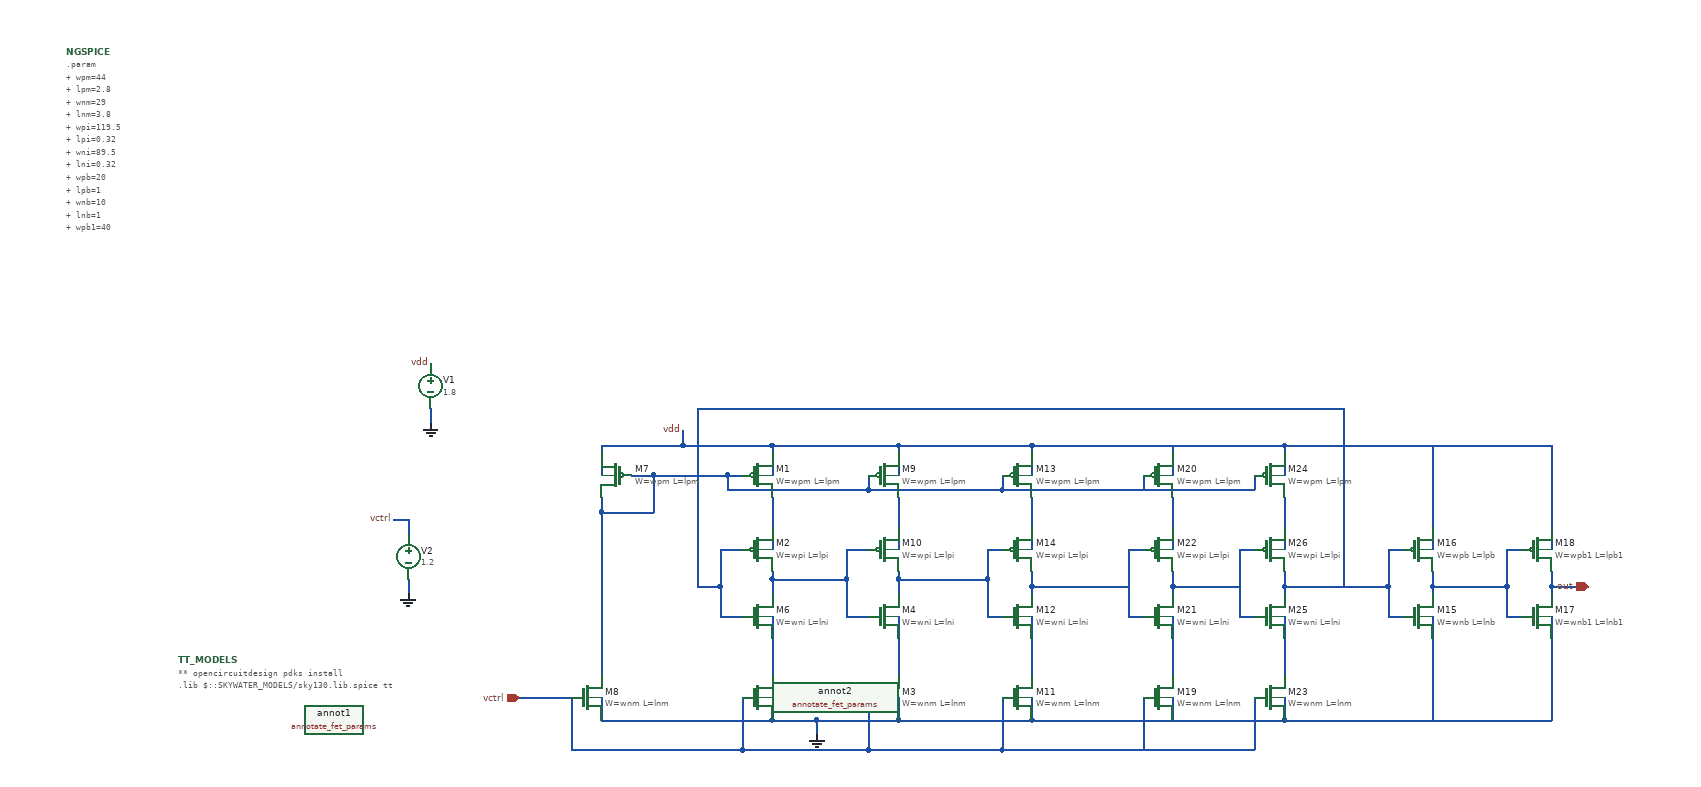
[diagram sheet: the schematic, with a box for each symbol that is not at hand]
v {xschem version=3.4.8RC file_version=1.3}
G {}
K {}
V {}
S {}
F {}
E {}
B 2 1400 -140 2200 260 {flags=graph
y1=-0.039
y2=1.9
ypos1=0
ypos2=2
divy=5
subdivy=1
unity=1
x1=7.7426134e-07
x2=8.4463009e-07
divx=5
subdivx=1
xlabmag=1.0
ylabmag=1.0
node=out
color=4
dataset=-1
unitx=1
logx=0
logy=0
hilight_wave=0}
N 1110 560 1110 580 {lab=#net1}
N 1110 450 1110 520 {lab=#net2}
N 1040 570 1040 610 {lab=#net3}
N 1040 520 1070 520 {lab=#net3}
N 1050 420 1070 420 {lab=#net4}
N 880 470 950 470 {lab=#net4}
N 950 420 950 470 {lab=#net4}
N 1070 720 1070 790 {lab=vctrl}
N 840 720 840 790 {lab=vctrl}
N 770 720 840 720 {lab=vctrl}
N 880 720 880 750 {lab=0}
N 880 750 1110 750 {lab=0}
N 1110 720 1110 750 {lab=0}
N 1040 610 1070 610 {lab=#net3}
N 880 380 880 420 {lab=vdd}
N 990 380 1110 380 {lab=vdd}
N 1110 380 1110 420 {lab=vdd}
N 1280 450 1280 520 {lab=#net5}
N 1240 720 1240 790 {lab=vctrl}
N 1280 720 1280 750 {lab=0}
N 1280 380 1280 420 {lab=vdd}
N 1110 560 1210 560 {lab=#net1}
N 1210 520 1210 560 {lab=#net1}
N 1210 520 1240 520 {lab=#net1}
N 1210 560 1210 610 {lab=#net1}
N 1210 610 1240 610 {lab=#net1}
N 1110 380 1280 380 {lab=vdd}
N 1460 450 1460 520 {lab=#net6}
N 1420 720 1420 790 {lab=vctrl}
N 1460 720 1460 750 {lab=0}
N 1460 380 1460 420 {lab=vdd}
N 1280 560 1400 560 {lab=#net7}
N 1400 520 1400 560 {lab=#net7}
N 1400 520 1420 520 {lab=#net7}
N 1400 560 1400 610 {lab=#net7}
N 1400 610 1420 610 {lab=#net7}
N 1540 570 1580 570 {lab=#net8}
N 1010 330 1010 570 {lab=#net3}
N 1010 570 1040 570 {lab=#net3}
N 1280 750 1460 750 {lab=0}
N 1240 790 1420 790 {lab=vctrl}
N 880 470 880 690 {lab=#net4}
N 990 360 990 380 {lab=vdd}
N 1280 380 1460 380 {lab=vdd}
N 1110 610 1110 700 {lab=#net9}
N 650 330 650 350 {lab=0}
N 600 480 620 480 {lab=vctrl}
N 620 480 620 500 {lab=vctrl}
N 620 560 620 580 {lab=0}
N 1050 420 1050 440 {lab=#net4}
N 1050 440 1240 440 {lab=#net4}
N 1240 420 1240 440 {lab=#net4}
N 1240 440 1420 440 {lab=#net4}
N 1420 420 1420 440 {lab=#net4}
N 1280 560 1280 580 {lab=#net7}
N 1280 610 1280 700 {lab=#net10}
N 1460 570 1460 580 {lab=#net8}
N 1460 610 1460 700 {lab=#net11}
N 1460 380 1640 380 {lab=vdd}
N 1010 330 1540 330 {lab=#net3}
N 1640 380 1800 380 {lab=vdd}
N 1640 750 1800 750 {lab=0}
N 880 450 880 470 {lab=#net4}
N 920 420 950 420 {lab=#net4}
N 840 790 1070 790 {lab=vctrl}
N 880 380 990 380 {lab=vdd}
N 1070 790 1240 790 {lab=vctrl}
N 1170 750 1280 750 {lab=0}
N 1110 550 1110 560 {lab=#net1}
N 1280 550 1280 560 {lab=#net7}
N 1460 550 1460 570 {lab=#net8}
N 1040 520 1040 570 {lab=#net3}
N 1110 750 1170 750 {lab=0}
N 950 420 1050 420 {lab=#net4}
N 1460 570 1540 570 {lab=#net8}
N 1460 750 1640 750 {lab=0}
N 1170 750 1170 770 {lab=0}
N 1940 520 1940 570 {lab=#net3}
N 1940 520 1960 520 {lab=#net3}
N 1940 570 1940 610 {lab=#net3}
N 1940 610 1960 610 {lab=#net3}
N 2000 570 2000 580 {lab=#net12}
N 2000 570 2100 570 {lab=#net12}
N 2100 520 2100 570 {lab=#net12}
N 2100 520 2120 520 {lab=#net12}
N 2100 570 2100 610 {lab=#net12}
N 2100 610 2120 610 {lab=#net12}
N 2160 570 2160 580 {lab=out}
N 2160 570 2210 570 {lab=out}
N 2000 550 2000 570 {lab=#net12}
N 2160 550 2160 570 {lab=out}
N 1650 450 1650 520 {lab=#net13}
N 1610 720 1610 790 {lab=vctrl}
N 1650 720 1650 750 {lab=0}
N 1650 380 1650 420 {lab=vdd}
N 1590 520 1590 560 {lab=#net8}
N 1590 520 1610 520 {lab=#net8}
N 1590 560 1590 610 {lab=#net8}
N 1590 610 1610 610 {lab=#net8}
N 1610 420 1610 440 {lab=#net4}
N 1650 570 1650 580 {lab=#net14}
N 1650 610 1650 700 {lab=#net15}
N 1650 550 1650 570 {lab=#net14}
N 1800 450 1800 520 {lab=#net16}
N 1760 720 1760 790 {lab=vctrl}
N 1800 720 1800 750 {lab=0}
N 1800 380 1800 420 {lab=vdd}
N 1740 520 1740 560 {lab=#net14}
N 1740 520 1760 520 {lab=#net14}
N 1740 560 1740 610 {lab=#net14}
N 1740 610 1760 610 {lab=#net14}
N 1760 420 1760 440 {lab=#net4}
N 1800 570 1800 580 {lab=#net3}
N 1800 610 1800 700 {lab=#net17}
N 1800 550 1800 570 {lab=#net3}
N 1800 570 1940 570 {lab=#net3}
N 1800 380 2160 380 {lab=vdd}
N 2160 380 2160 490 {lab=vdd}
N 2000 380 2000 490 {lab=vdd}
N 2000 490 2000 520 {lab=vdd}
N 2160 490 2160 520 {lab=vdd}
N 2000 610 2000 640 {lab=0}
N 2160 610 2160 640 {lab=0}
N 1800 750 2160 750 {lab=0}
N 2160 640 2160 750 {lab=0}
N 2000 640 2000 750 {lab=0}
N 1420 790 1760 790 {lab=vctrl}
N 1420 440 1760 440 {lab=#net4}
N 1580 570 1590 570 {lab=#net8}
N 1650 570 1740 570 {lab=#net14}
N 1880 330 1880 570 {lab=#net3}
N 1540 330 1880 330 {lab=#net3}
C {sky130_fd_pr/pfet_01v8.sym} 900 420 0 1 {name=M7
W="wpm"
L="lpm"
nf=1
mult=1
ad="expr('int((@nf + 1)/2) * @W / @nf * 0.29')"
pd="expr('2*int((@nf + 1)/2) * (@W / @nf + 0.29)')"
as="expr('int((@nf + 2)/2) * @W / @nf * 0.29')"
ps="expr('2*int((@nf + 2)/2) * (@W / @nf + 0.29)')"
nrd="expr('0.29 / @W ')" nrs="expr('0.29 / @W ')"
sa=0 sb=0 sd=0
model=pfet_01v8
spiceprefix=X
}
C {sky130_fd_pr/nfet_01v8.sym} 860 720 0 0 {name=M8
W="wnm"
L="lnm"
nf=1 
mult=1
ad="expr('int((@nf + 1)/2) * @W / @nf * 0.29')"
pd="expr('2*int((@nf + 1)/2) * (@W / @nf + 0.29)')"
as="expr('int((@nf + 2)/2) * @W / @nf * 0.29')"
ps="expr('2*int((@nf + 2)/2) * (@W / @nf + 0.29)')"
nrd="expr('0.29 / @W ')" nrs="expr('0.29 / @W ')"
sa=0 sb=0 sd=0
model=nfet_01v8
spiceprefix=X
}
C {sky130_fd_pr/nfet_01v8.sym} 1090 720 0 0 {name=M5
W="wnm"
L="lnm"
nf=1 
mult=1
ad="expr('int((@nf + 1)/2) * @W / @nf * 0.29')"
pd="expr('2*int((@nf + 1)/2) * (@W / @nf + 0.29)')"
as="expr('int((@nf + 2)/2) * @W / @nf * 0.29')"
ps="expr('2*int((@nf + 2)/2) * (@W / @nf + 0.29)')"
nrd="expr('0.29 / @W ')" nrs="expr('0.29 / @W ')"
sa=0 sb=0 sd=0
model=nfet_01v8
spiceprefix=X
}
C {sky130_fd_pr/nfet_01v8.sym} 1090 610 0 0 {name=M6
W="wni"
L="lni"
nf=1 
mult=1
ad="expr('int((@nf + 1)/2) * @W / @nf * 0.29')"
pd="expr('2*int((@nf + 1)/2) * (@W / @nf + 0.29)')"
as="expr('int((@nf + 2)/2) * @W / @nf * 0.29')"
ps="expr('2*int((@nf + 2)/2) * (@W / @nf + 0.29)')"
nrd="expr('0.29 / @W ')" nrs="expr('0.29 / @W ')"
sa=0 sb=0 sd=0
model=nfet_01v8
spiceprefix=X
}
C {sky130_fd_pr/pfet_01v8.sym} 1090 420 0 0 {name=M1
W="wpm"
L="lpm"
nf=1
mult=1
ad="expr('int((@nf + 1)/2) * @W / @nf * 0.29')"
pd="expr('2*int((@nf + 1)/2) * (@W / @nf + 0.29)')"
as="expr('int((@nf + 2)/2) * @W / @nf * 0.29')"
ps="expr('2*int((@nf + 2)/2) * (@W / @nf + 0.29)')"
nrd="expr('0.29 / @W ')" nrs="expr('0.29 / @W ')"
sa=0 sb=0 sd=0
model=pfet_01v8
spiceprefix=X
}
C {sky130_fd_pr/pfet_01v8.sym} 1090 520 0 0 {name=M2
W="wpi"
L="lpi"
nf=1
mult=1
ad="expr('int((@nf + 1)/2) * @W / @nf * 0.29')"
pd="expr('2*int((@nf + 1)/2) * (@W / @nf + 0.29)')"
as="expr('int((@nf + 2)/2) * @W / @nf * 0.29')"
ps="expr('2*int((@nf + 2)/2) * (@W / @nf + 0.29)')"
nrd="expr('0.29 / @W ')" nrs="expr('0.29 / @W ')"
sa=0 sb=0 sd=0
model=pfet_01v8
spiceprefix=X
}
C {sky130_fd_pr/nfet_01v8.sym} 1260 720 0 0 {name=M3
W="wnm"
L="lnm"
nf=1 
mult=1
ad="expr('int((@nf + 1)/2) * @W / @nf * 0.29')"
pd="expr('2*int((@nf + 1)/2) * (@W / @nf + 0.29)')"
as="expr('int((@nf + 2)/2) * @W / @nf * 0.29')"
ps="expr('2*int((@nf + 2)/2) * (@W / @nf + 0.29)')"
nrd="expr('0.29 / @W ')" nrs="expr('0.29 / @W ')"
sa=0 sb=0 sd=0
model=nfet_01v8
spiceprefix=X
}
C {sky130_fd_pr/pfet_01v8.sym} 1260 420 0 0 {name=M9
W="wpm"
L="lpm"
nf=1
mult=1
ad="expr('int((@nf + 1)/2) * @W / @nf * 0.29')"
pd="expr('2*int((@nf + 1)/2) * (@W / @nf + 0.29)')"
as="expr('int((@nf + 2)/2) * @W / @nf * 0.29')"
ps="expr('2*int((@nf + 2)/2) * (@W / @nf + 0.29)')"
nrd="expr('0.29 / @W ')" nrs="expr('0.29 / @W ')"
sa=0 sb=0 sd=0
model=pfet_01v8
spiceprefix=X
}
C {sky130_fd_pr/nfet_01v8.sym} 1440 720 0 0 {name=M11
W="wnm"
L="lnm"
nf=1 
mult=1
ad="expr('int((@nf + 1)/2) * @W / @nf * 0.29')"
pd="expr('2*int((@nf + 1)/2) * (@W / @nf + 0.29)')"
as="expr('int((@nf + 2)/2) * @W / @nf * 0.29')"
ps="expr('2*int((@nf + 2)/2) * (@W / @nf + 0.29)')"
nrd="expr('0.29 / @W ')" nrs="expr('0.29 / @W ')"
sa=0 sb=0 sd=0
model=nfet_01v8
spiceprefix=X
}
C {sky130_fd_pr/pfet_01v8.sym} 1440 420 0 0 {name=M13
W="wpm"
L="lpm"
nf=1
mult=1
ad="expr('int((@nf + 1)/2) * @W / @nf * 0.29')"
pd="expr('2*int((@nf + 1)/2) * (@W / @nf + 0.29)')"
as="expr('int((@nf + 2)/2) * @W / @nf * 0.29')"
ps="expr('2*int((@nf + 2)/2) * (@W / @nf + 0.29)')"
nrd="expr('0.29 / @W ')" nrs="expr('0.29 / @W ')"
sa=0 sb=0 sd=0
model=pfet_01v8
spiceprefix=X
}
C {ipin.sym} 770 720 0 0 {name=p1 lab=vctrl}
C {code_shown.sym} 160 -150 0 0 {name=NGSPICE only_toplevel=false value="
.param
+ wpm=44
+ lpm=2.8
+ wnm=29
+ lnm=3.8
+ wpi=119.5
+ lpi=0.32
+ wni=89.5
+ lni=0.32
+ wpb=20
+ lpb=1
+ wnb=10
+ lnb=1
+ wpb1=40
+ lpb1=1
+ wnb1=20
+ lnb1=1
.control
tran 1n 2u
write vco_5.raw
.endc
"}
C {gnd.sym} 1170 770 0 0 {name=l2 lab=0}
C {vsource.sym} 650 300 0 0 {name=V1 value=1.8 savecurrent=false}
C {lab_pin.sym} 650 270 0 0 {name=p4 sig_type=std_logic lab=vdd}
C {gnd.sym} 650 350 0 0 {name=l3 lab=0}
C {vsource.sym} 620 530 0 0 {name=V2 value=1.2 savecurrent=false}
C {gnd.sym} 620 580 0 0 {name=l4 lab=0}
C {sky130_fd_pr/nfet_01v8.sym} 1260 610 0 0 {name=M4
W="wni"
L="lni"
nf=1 
mult=1
ad="expr('int((@nf + 1)/2) * @W / @nf * 0.29')"
pd="expr('2*int((@nf + 1)/2) * (@W / @nf + 0.29)')"
as="expr('int((@nf + 2)/2) * @W / @nf * 0.29')"
ps="expr('2*int((@nf + 2)/2) * (@W / @nf + 0.29)')"
nrd="expr('0.29 / @W ')" nrs="expr('0.29 / @W ')"
sa=0 sb=0 sd=0
model=nfet_01v8
spiceprefix=X
}
C {sky130_fd_pr/pfet_01v8.sym} 1260 520 0 0 {name=M10
W="wpi"
L="lpi"
nf=1
mult=1
ad="expr('int((@nf + 1)/2) * @W / @nf * 0.29')"
pd="expr('2*int((@nf + 1)/2) * (@W / @nf + 0.29)')"
as="expr('int((@nf + 2)/2) * @W / @nf * 0.29')"
ps="expr('2*int((@nf + 2)/2) * (@W / @nf + 0.29)')"
nrd="expr('0.29 / @W ')" nrs="expr('0.29 / @W ')"
sa=0 sb=0 sd=0
model=pfet_01v8
spiceprefix=X
}
C {sky130_fd_pr/nfet_01v8.sym} 1440 610 0 0 {name=M12
W="wni"
L="lni"
nf=1 
mult=1
ad="expr('int((@nf + 1)/2) * @W / @nf * 0.29')"
pd="expr('2*int((@nf + 1)/2) * (@W / @nf + 0.29)')"
as="expr('int((@nf + 2)/2) * @W / @nf * 0.29')"
ps="expr('2*int((@nf + 2)/2) * (@W / @nf + 0.29)')"
nrd="expr('0.29 / @W ')" nrs="expr('0.29 / @W ')"
sa=0 sb=0 sd=0
model=nfet_01v8
spiceprefix=X
}
C {sky130_fd_pr/pfet_01v8.sym} 1440 520 0 0 {name=M14
W="wpi"
L="lpi"
nf=1
mult=1
ad="expr('int((@nf + 1)/2) * @W / @nf * 0.29')"
pd="expr('2*int((@nf + 1)/2) * (@W / @nf + 0.29)')"
as="expr('int((@nf + 2)/2) * @W / @nf * 0.29')"
ps="expr('2*int((@nf + 2)/2) * (@W / @nf + 0.29)')"
nrd="expr('0.29 / @W ')" nrs="expr('0.29 / @W ')"
sa=0 sb=0 sd=0
model=pfet_01v8
spiceprefix=X
}
C {lab_pin.sym} 600 480 0 0 {name=p5 sig_type=std_logic lab=vctrl}
C {lab_pin.sym} 990 360 0 0 {name=p3 sig_type=std_logic lab=vdd}
C {devices/code.sym} 310 670 0 0 {name=TT_MODELS
only_toplevel=true
format="tcleval( @value )"
value="
** opencircuitdesign pdks install
.lib $::SKYWATER_MODELS/sky130.lib.spice tt
"
spice_ignore=false}
C {sky130_fd_pr/annotate_fet_params.sym} 520 750 0 0 {name=annot1 ref=M7}
C {sky130_fd_pr/annotate_fet_params.sym} 610 750 0 0 {name=annot2 ref=M8}
C {launcher.sym} 1190 170 0 0 {name=h5
descr="load waves"
tclcommand="xschem raw_read $netlist_dir/vco_5.raw tran"
}
C {iopin.sym} 2210 570 0 0 {name=p2 lab=out}
C {sky130_fd_pr/nfet_01v8.sym} 1980 610 0 0 {name=M15
W="wnb"
L="lnb"
nf=1 
mult=1
ad="expr('int((@nf + 1)/2) * @W / @nf * 0.29')"
pd="expr('2*int((@nf + 1)/2) * (@W / @nf + 0.29)')"
as="expr('int((@nf + 2)/2) * @W / @nf * 0.29')"
ps="expr('2*int((@nf + 2)/2) * (@W / @nf + 0.29)')"
nrd="expr('0.29 / @W ')" nrs="expr('0.29 / @W ')"
sa=0 sb=0 sd=0
model=nfet_01v8
spiceprefix=X
}
C {sky130_fd_pr/pfet_01v8.sym} 1980 520 0 0 {name=M16
W="wpb"
L="lpb"
nf=1
mult=1
ad="expr('int((@nf + 1)/2) * @W / @nf * 0.29')"
pd="expr('2*int((@nf + 1)/2) * (@W / @nf + 0.29)')"
as="expr('int((@nf + 2)/2) * @W / @nf * 0.29')"
ps="expr('2*int((@nf + 2)/2) * (@W / @nf + 0.29)')"
nrd="expr('0.29 / @W ')" nrs="expr('0.29 / @W ')"
sa=0 sb=0 sd=0
model=pfet_01v8
spiceprefix=X
}
C {sky130_fd_pr/nfet_01v8.sym} 2140 610 0 0 {name=M17
W="wnb1"
L="lnb1"
nf=1 
mult=1
ad="expr('int((@nf + 1)/2) * @W / @nf * 0.29')"
pd="expr('2*int((@nf + 1)/2) * (@W / @nf + 0.29)')"
as="expr('int((@nf + 2)/2) * @W / @nf * 0.29')"
ps="expr('2*int((@nf + 2)/2) * (@W / @nf + 0.29)')"
nrd="expr('0.29 / @W ')" nrs="expr('0.29 / @W ')"
sa=0 sb=0 sd=0
model=nfet_01v8
spiceprefix=X
}
C {sky130_fd_pr/pfet_01v8.sym} 2140 520 0 0 {name=M18
W="wpb1"
L="lpb1"
nf=1
mult=1
ad="expr('int((@nf + 1)/2) * @W / @nf * 0.29')"
pd="expr('2*int((@nf + 1)/2) * (@W / @nf + 0.29)')"
as="expr('int((@nf + 2)/2) * @W / @nf * 0.29')"
ps="expr('2*int((@nf + 2)/2) * (@W / @nf + 0.29)')"
nrd="expr('0.29 / @W ')" nrs="expr('0.29 / @W ')"
sa=0 sb=0 sd=0
model=pfet_01v8
spiceprefix=X
}
C {sky130_fd_pr/nfet_01v8.sym} 1630 720 0 0 {name=M19
W="wnm"
L="lnm"
nf=1 
mult=1
ad="expr('int((@nf + 1)/2) * @W / @nf * 0.29')"
pd="expr('2*int((@nf + 1)/2) * (@W / @nf + 0.29)')"
as="expr('int((@nf + 2)/2) * @W / @nf * 0.29')"
ps="expr('2*int((@nf + 2)/2) * (@W / @nf + 0.29)')"
nrd="expr('0.29 / @W ')" nrs="expr('0.29 / @W ')"
sa=0 sb=0 sd=0
model=nfet_01v8
spiceprefix=X
}
C {sky130_fd_pr/pfet_01v8.sym} 1630 420 0 0 {name=M20
W="wpm"
L="lpm"
nf=1
mult=1
ad="expr('int((@nf + 1)/2) * @W / @nf * 0.29')"
pd="expr('2*int((@nf + 1)/2) * (@W / @nf + 0.29)')"
as="expr('int((@nf + 2)/2) * @W / @nf * 0.29')"
ps="expr('2*int((@nf + 2)/2) * (@W / @nf + 0.29)')"
nrd="expr('0.29 / @W ')" nrs="expr('0.29 / @W ')"
sa=0 sb=0 sd=0
model=pfet_01v8
spiceprefix=X
}
C {sky130_fd_pr/nfet_01v8.sym} 1630 610 0 0 {name=M21
W="wni"
L="lni"
nf=1 
mult=1
ad="expr('int((@nf + 1)/2) * @W / @nf * 0.29')"
pd="expr('2*int((@nf + 1)/2) * (@W / @nf + 0.29)')"
as="expr('int((@nf + 2)/2) * @W / @nf * 0.29')"
ps="expr('2*int((@nf + 2)/2) * (@W / @nf + 0.29)')"
nrd="expr('0.29 / @W ')" nrs="expr('0.29 / @W ')"
sa=0 sb=0 sd=0
model=nfet_01v8
spiceprefix=X
}
C {sky130_fd_pr/pfet_01v8.sym} 1630 520 0 0 {name=M22
W="wpi"
L="lpi"
nf=1
mult=1
ad="expr('int((@nf + 1)/2) * @W / @nf * 0.29')"
pd="expr('2*int((@nf + 1)/2) * (@W / @nf + 0.29)')"
as="expr('int((@nf + 2)/2) * @W / @nf * 0.29')"
ps="expr('2*int((@nf + 2)/2) * (@W / @nf + 0.29)')"
nrd="expr('0.29 / @W ')" nrs="expr('0.29 / @W ')"
sa=0 sb=0 sd=0
model=pfet_01v8
spiceprefix=X
}
C {sky130_fd_pr/nfet_01v8.sym} 1780 720 0 0 {name=M23
W="wnm"
L="lnm"
nf=1 
mult=1
ad="expr('int((@nf + 1)/2) * @W / @nf * 0.29')"
pd="expr('2*int((@nf + 1)/2) * (@W / @nf + 0.29)')"
as="expr('int((@nf + 2)/2) * @W / @nf * 0.29')"
ps="expr('2*int((@nf + 2)/2) * (@W / @nf + 0.29)')"
nrd="expr('0.29 / @W ')" nrs="expr('0.29 / @W ')"
sa=0 sb=0 sd=0
model=nfet_01v8
spiceprefix=X
}
C {sky130_fd_pr/pfet_01v8.sym} 1780 420 0 0 {name=M24
W="wpm"
L="lpm"
nf=1
mult=1
ad="expr('int((@nf + 1)/2) * @W / @nf * 0.29')"
pd="expr('2*int((@nf + 1)/2) * (@W / @nf + 0.29)')"
as="expr('int((@nf + 2)/2) * @W / @nf * 0.29')"
ps="expr('2*int((@nf + 2)/2) * (@W / @nf + 0.29)')"
nrd="expr('0.29 / @W ')" nrs="expr('0.29 / @W ')"
sa=0 sb=0 sd=0
model=pfet_01v8
spiceprefix=X
}
C {sky130_fd_pr/nfet_01v8.sym} 1780 610 0 0 {name=M25
W="wni"
L="lni"
nf=1 
mult=1
ad="expr('int((@nf + 1)/2) * @W / @nf * 0.29')"
pd="expr('2*int((@nf + 1)/2) * (@W / @nf + 0.29)')"
as="expr('int((@nf + 2)/2) * @W / @nf * 0.29')"
ps="expr('2*int((@nf + 2)/2) * (@W / @nf + 0.29)')"
nrd="expr('0.29 / @W ')" nrs="expr('0.29 / @W ')"
sa=0 sb=0 sd=0
model=nfet_01v8
spiceprefix=X
}
C {sky130_fd_pr/pfet_01v8.sym} 1780 520 0 0 {name=M26
W="wpi"
L="lpi"
nf=1
mult=1
ad="expr('int((@nf + 1)/2) * @W / @nf * 0.29')"
pd="expr('2*int((@nf + 1)/2) * (@W / @nf + 0.29)')"
as="expr('int((@nf + 2)/2) * @W / @nf * 0.29')"
ps="expr('2*int((@nf + 2)/2) * (@W / @nf + 0.29)')"
nrd="expr('0.29 / @W ')" nrs="expr('0.29 / @W ')"
sa=0 sb=0 sd=0
model=pfet_01v8
spiceprefix=X
}
